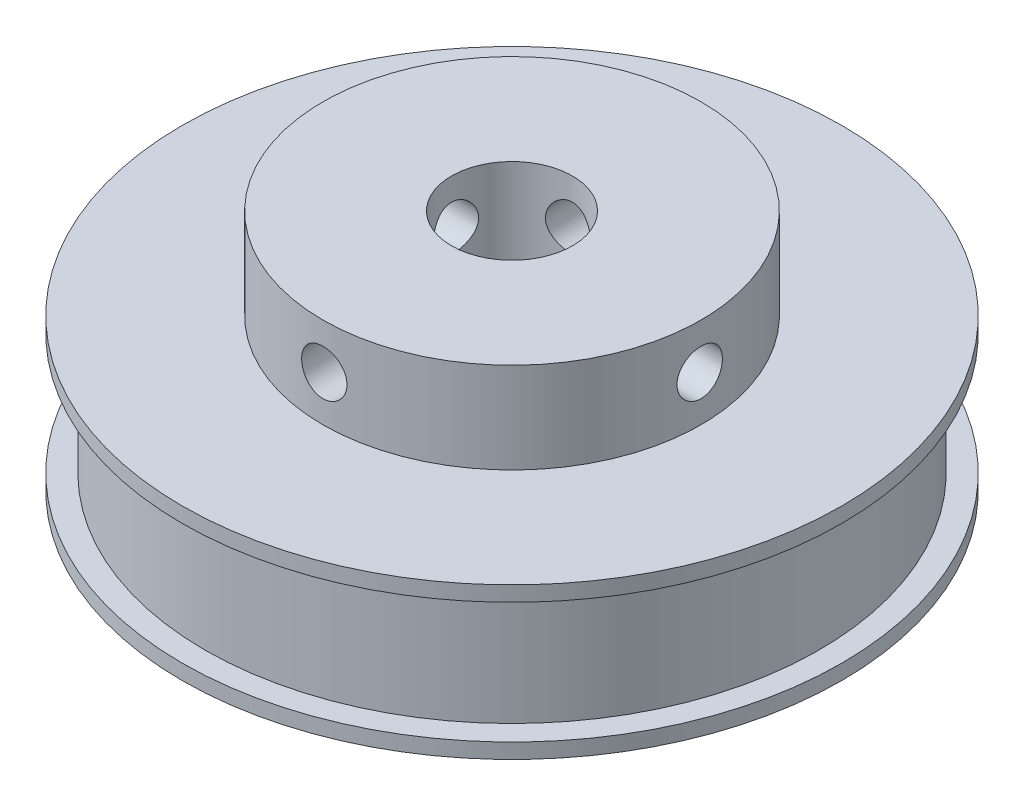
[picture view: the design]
ISO-10303-21;
HEADER;
FILE_DESCRIPTION(('STEP AP214'),'2;1');
FILE_NAME('part.step','',(''),(''),'','','');
FILE_SCHEMA(('AUTOMOTIVE_DESIGN { 1 0 10303 214 1 1 1 1 }'));
ENDSEC;
DATA;
#1=APPLICATION_CONTEXT('core data for automotive mechanical design processes');
#2=APPLICATION_PROTOCOL_DEFINITION('international standard','automotive_design',2000,#1);
#3=PRODUCT_CONTEXT('',#1,'mechanical');
#4=PRODUCT('Part','Part','',(#3));
#5=PRODUCT_RELATED_PRODUCT_CATEGORY('part','',(#4));
#6=PRODUCT_DEFINITION_FORMATION('','',#4);
#7=PRODUCT_DEFINITION_CONTEXT('part definition',#1,'design');
#8=PRODUCT_DEFINITION('design','',#6,#7);
#9=PRODUCT_DEFINITION_SHAPE('','',#8);
#10=(LENGTH_UNIT() NAMED_UNIT(*) SI_UNIT(.MILLI.,.METRE.));
#11=(NAMED_UNIT(*) PLANE_ANGLE_UNIT() SI_UNIT($,.RADIAN.));
#12=(NAMED_UNIT(*) SI_UNIT($,.STERADIAN.) SOLID_ANGLE_UNIT());
#13=UNCERTAINTY_MEASURE_WITH_UNIT(LENGTH_MEASURE(1.E-05),#10,'distance_accuracy_value','');
#14=(GEOMETRIC_REPRESENTATION_CONTEXT(3) GLOBAL_UNCERTAINTY_ASSIGNED_CONTEXT((#13)) GLOBAL_UNIT_ASSIGNED_CONTEXT((#10,
#11,#12)) REPRESENTATION_CONTEXT('',''));
#15=CARTESIAN_POINT('',(0.,0.,0.));
#16=DIRECTION('',(0.,0.,1.));
#17=DIRECTION('',(1.,0.,0.));
#18=AXIS2_PLACEMENT_3D('',#15,#16,#17);
#19=CARTESIAN_POINT('',(0.,16.,0.));
#20=DIRECTION('',(0.,-1.,0.));
#21=DIRECTION('',(0.,0.,-1.));
#22=AXIS2_PLACEMENT_3D('',#19,#20,#21);
#23=CYLINDRICAL_SURFACE('',#22,21.8);
#24=CARTESIAN_POINT('',(0.,0.,0.));
#25=DIRECTION('',(0.,1.,0.));
#26=DIRECTION('',(0.,0.,1.));
#27=AXIS2_PLACEMENT_3D('',#24,#25,#26);
#28=CIRCLE('',#27,21.8);
#29=CARTESIAN_POINT('',(0.,0.,21.8));
#30=VERTEX_POINT('',#29);
#31=EDGE_CURVE('E11',#30,#30,#28,.T.);
#32=ORIENTED_EDGE('',*,*,#31,.T.);
#33=EDGE_LOOP('',(#32));
#34=FACE_BOUND('',#33,.T.);
#35=CARTESIAN_POINT('',(0.,1.,0.));
#36=DIRECTION('',(0.,1.,0.));
#37=DIRECTION('',(0.,0.,1.));
#38=AXIS2_PLACEMENT_3D('',#35,#36,#37);
#39=CIRCLE('',#38,21.8);
#40=CARTESIAN_POINT('',(0.,1.,21.8));
#41=VERTEX_POINT('',#40);
#42=EDGE_CURVE('E69',#41,#41,#39,.T.);
#43=ORIENTED_EDGE('',*,*,#42,.F.);
#44=EDGE_LOOP('',(#43));
#45=FACE_BOUND('',#44,.T.);
#46=ADVANCED_FACE('F41',(#34,#45),#23,.T.);
#47=CARTESIAN_POINT('',(0.,9.,0.));
#48=DIRECTION('',(0.,1.,0.));
#49=DIRECTION('',(0.,0.,1.));
#50=AXIS2_PLACEMENT_3D('',#47,#48,#49);
#51=CIRCLE('',#50,21.8);
#52=CARTESIAN_POINT('',(0.,9.,21.8));
#53=VERTEX_POINT('',#52);
#54=EDGE_CURVE('E66',#53,#53,#51,.T.);
#55=ORIENTED_EDGE('',*,*,#54,.T.);
#56=EDGE_LOOP('',(#55));
#57=FACE_BOUND('',#56,.T.);
#58=CARTESIAN_POINT('',(0.,10.,0.));
#59=DIRECTION('',(0.,1.,0.));
#60=DIRECTION('',(0.,0.,1.));
#61=AXIS2_PLACEMENT_3D('',#58,#59,#60);
#62=CIRCLE('',#61,21.8);
#63=CARTESIAN_POINT('',(0.,10.,21.8));
#64=VERTEX_POINT('',#63);
#65=EDGE_CURVE('E65',#64,#64,#62,.T.);
#66=ORIENTED_EDGE('',*,*,#65,.F.);
#67=EDGE_LOOP('',(#66));
#68=FACE_BOUND('',#67,.T.);
#69=ADVANCED_FACE('F43',(#57,#68),#23,.T.);
#70=CARTESIAN_POINT('',(0.,16.,0.));
#71=DIRECTION('',(0.,1.,0.));
#72=DIRECTION('',(0.,0.,1.));
#73=AXIS2_PLACEMENT_3D('',#70,#71,#72);
#74=PLANE('',#73);
#75=CARTESIAN_POINT('',(0.,16.,0.));
#76=DIRECTION('',(0.,1.,0.));
#77=DIRECTION('',(0.,0.,1.));
#78=AXIS2_PLACEMENT_3D('',#75,#76,#77);
#79=CIRCLE('',#78,4.);
#80=CARTESIAN_POINT('',(0.,16.,4.));
#81=VERTEX_POINT('',#80);
#82=EDGE_CURVE('E56',#81,#81,#79,.T.);
#83=ORIENTED_EDGE('',*,*,#82,.F.);
#84=EDGE_LOOP('',(#83));
#85=FACE_BOUND('',#84,.T.);
#86=CARTESIAN_POINT('',(0.,16.,0.));
#87=DIRECTION('',(0.,1.,0.));
#88=DIRECTION('',(0.,0.,1.));
#89=AXIS2_PLACEMENT_3D('',#86,#87,#88);
#90=CIRCLE('',#89,12.5);
#91=CARTESIAN_POINT('',(0.,16.,12.5));
#92=VERTEX_POINT('',#91);
#93=EDGE_CURVE('E73',#92,#92,#90,.T.);
#94=ORIENTED_EDGE('',*,*,#93,.T.);
#95=EDGE_LOOP('',(#94));
#96=FACE_BOUND('',#95,.T.);
#97=ADVANCED_FACE('F127',(#85,#96),#74,.T.);
#98=CARTESIAN_POINT('',(0.,0.,0.));
#99=DIRECTION('',(0.,1.,0.));
#100=DIRECTION('',(0.,0.,1.));
#101=AXIS2_PLACEMENT_3D('',#98,#99,#100);
#102=PLANE('',#101);
#103=CARTESIAN_POINT('',(0.,0.,0.));
#104=DIRECTION('',(0.,1.,0.));
#105=DIRECTION('',(0.,0.,1.));
#106=AXIS2_PLACEMENT_3D('',#103,#104,#105);
#107=CIRCLE('',#106,4.);
#108=CARTESIAN_POINT('',(0.,0.,4.));
#109=VERTEX_POINT('',#108);
#110=EDGE_CURVE('E53',#109,#109,#107,.T.);
#111=ORIENTED_EDGE('',*,*,#110,.T.);
#112=EDGE_LOOP('',(#111));
#113=FACE_BOUND('',#112,.T.);
#114=ORIENTED_EDGE('',*,*,#31,.F.);
#115=EDGE_LOOP('',(#114));
#116=FACE_BOUND('',#115,.T.);
#117=ADVANCED_FACE('F130',(#113,#116),#102,.F.);
#118=CARTESIAN_POINT('',(0.,0.,0.));
#119=DIRECTION('',(0.,1.,0.));
#120=DIRECTION('',(0.,0.,1.));
#121=AXIS2_PLACEMENT_3D('',#118,#119,#120);
#122=CYLINDRICAL_SURFACE('',#121,4.);
#123=CARTESIAN_POINT('',(0.,11.5,4.));
#124=CARTESIAN_POINT('',(0.0812350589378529,11.4999970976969,4.00000217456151));
#125=CARTESIAN_POINT('',(0.162450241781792,11.5066197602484,3.99750379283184));
#126=CARTESIAN_POINT('',(0.322453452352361,11.5328281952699,3.98778696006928));
#127=CARTESIAN_POINT('',(0.401241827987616,11.5524121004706,3.98056918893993));
#128=CARTESIAN_POINT('',(0.554060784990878,11.6037530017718,3.96218832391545));
#129=CARTESIAN_POINT('',(0.628100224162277,11.6354865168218,3.9510328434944));
#130=CARTESIAN_POINT('',(0.769799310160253,11.7101064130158,3.92588767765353));
#131=CARTESIAN_POINT('',(0.837457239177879,11.7529957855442,3.91189723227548));
#132=CARTESIAN_POINT('',(0.967346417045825,11.8506125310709,3.88186246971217));
#133=CARTESIAN_POINT('',(1.02927073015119,11.9057302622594,3.86576002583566));
#134=CARTESIAN_POINT('',(1.14324421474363,12.0254104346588,3.83360220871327));
#135=CARTESIAN_POINT('',(1.19529036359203,12.0899757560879,3.81754685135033));
#136=CARTESIAN_POINT('',(1.28998202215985,12.2297174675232,3.78662470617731));
#137=CARTESIAN_POINT('',(1.3321939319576,12.3052043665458,3.77182648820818));
#138=CARTESIAN_POINT('',(1.40318646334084,12.4628483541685,3.74599860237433));
#139=CARTESIAN_POINT('',(1.43197244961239,12.5450027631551,3.73496742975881));
#140=CARTESIAN_POINT('',(1.47408431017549,12.7101167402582,3.71854412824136));
#141=CARTESIAN_POINT('',(1.48799593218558,12.7929050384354,3.71293924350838));
#142=CARTESIAN_POINT('',(1.50179556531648,12.9598161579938,3.70738061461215));
#143=CARTESIAN_POINT('',(1.5016893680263,13.0439384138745,3.70742453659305));
#144=CARTESIAN_POINT('',(1.48790429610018,13.205769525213,3.71297511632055));
#145=CARTESIAN_POINT('',(1.47503808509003,13.2835609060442,3.71815468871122));
#146=CARTESIAN_POINT('',(1.4374416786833,13.4357871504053,3.73284938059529));
#147=CARTESIAN_POINT('',(1.41270969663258,13.5102215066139,3.74236515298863));
#148=CARTESIAN_POINT('',(1.35163748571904,13.6552770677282,3.76485702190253));
#149=CARTESIAN_POINT('',(1.31508648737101,13.7257994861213,3.77789517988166));
#150=CARTESIAN_POINT('',(1.23156073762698,13.859945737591,3.80594210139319));
#151=CARTESIAN_POINT('',(1.18458238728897,13.9235671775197,3.82095154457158));
#152=CARTESIAN_POINT('',(1.07781780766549,14.0466036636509,3.85248038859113));
#153=CARTESIAN_POINT('',(1.01738298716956,14.1054486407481,3.86903347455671));
#154=CARTESIAN_POINT('',(0.887312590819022,14.2123379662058,3.90091728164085));
#155=CARTESIAN_POINT('',(0.817675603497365,14.2603806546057,3.91624781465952));
#156=CARTESIAN_POINT('',(0.66972343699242,14.3449303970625,3.9442639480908));
#157=CARTESIAN_POINT('',(0.591290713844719,14.3812475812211,3.95690498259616));
#158=CARTESIAN_POINT('',(0.428836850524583,14.43998260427,3.97778718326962));
#159=CARTESIAN_POINT('',(0.344818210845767,14.4624066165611,3.98603030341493));
#160=CARTESIAN_POINT('',(0.178375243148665,14.4916227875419,3.99684443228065));
#161=CARTESIAN_POINT('',(0.0961036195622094,14.4991826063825,3.99969369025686));
#162=CARTESIAN_POINT('',(-0.0685724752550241,14.5006910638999,4.00025893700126));
#163=CARTESIAN_POINT('',(-0.150976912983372,14.4946427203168,3.99797606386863));
#164=CARTESIAN_POINT('',(-0.310262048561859,14.4696899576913,3.98871709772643));
#165=CARTESIAN_POINT('',(-0.387233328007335,14.4512884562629,3.98192470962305));
#166=CARTESIAN_POINT('',(-0.53694175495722,14.4028139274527,3.96451477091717));
#167=CARTESIAN_POINT('',(-0.609678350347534,14.372739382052,3.9538967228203));
#168=CARTESIAN_POINT('',(-0.751247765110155,14.3008135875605,3.92949624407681));
#169=CARTESIAN_POINT('',(-0.819903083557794,14.2586422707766,3.91563000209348));
#170=CARTESIAN_POINT('',(-0.949392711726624,14.1640818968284,3.88626671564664));
#171=CARTESIAN_POINT('',(-1.01022412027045,14.1116890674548,3.87076907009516));
#172=CARTESIAN_POINT('',(-1.12603079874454,13.9945958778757,3.8387332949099));
#173=CARTESIAN_POINT('',(-1.18046154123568,13.9293578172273,3.82218696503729));
#174=CARTESIAN_POINT('',(-1.27771050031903,13.7903486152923,3.79078815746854));
#175=CARTESIAN_POINT('',(-1.32052767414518,13.7165767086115,3.77593583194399));
#176=CARTESIAN_POINT('',(-1.39337773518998,13.5619840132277,3.74966829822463));
#177=CARTESIAN_POINT('',(-1.42335685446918,13.4811352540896,3.73826760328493));
#178=CARTESIAN_POINT('',(-1.46907883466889,13.3149902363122,3.72054032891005));
#179=CARTESIAN_POINT('',(-1.48483050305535,13.2296967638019,3.71421061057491));
#180=CARTESIAN_POINT('',(-1.50086347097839,13.0629838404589,3.70775894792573));
#181=CARTESIAN_POINT('',(-1.50207331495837,12.9816673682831,3.70726444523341));
#182=CARTESIAN_POINT('',(-1.49136715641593,12.8200546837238,3.71158412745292));
#183=CARTESIAN_POINT('',(-1.47945239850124,12.7397583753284,3.71639780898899));
#184=CARTESIAN_POINT('',(-1.44355815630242,12.5849527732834,3.73048141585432));
#185=CARTESIAN_POINT('',(-1.41995798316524,12.5103416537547,3.73961085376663));
#186=CARTESIAN_POINT('',(-1.3616969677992,12.3660944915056,3.76121548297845));
#187=CARTESIAN_POINT('',(-1.32703332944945,12.2964597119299,3.77369151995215));
#188=CARTESIAN_POINT('',(-1.24552075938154,12.1601732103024,3.80139723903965));
#189=CARTESIAN_POINT('',(-1.1981283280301,12.0938692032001,3.81673698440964));
#190=CARTESIAN_POINT('',(-1.09334485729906,11.9698584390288,3.84806246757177));
#191=CARTESIAN_POINT('',(-1.03595064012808,11.9121544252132,3.86404840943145));
#192=CARTESIAN_POINT('',(-0.909080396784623,11.8037980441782,3.89590424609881));
#193=CARTESIAN_POINT('',(-0.839118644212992,11.7536962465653,3.91172104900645));
#194=CARTESIAN_POINT('',(-0.691213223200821,11.6659773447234,3.94054514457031));
#195=CARTESIAN_POINT('',(-0.613268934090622,11.6283612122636,3.95355221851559));
#196=CARTESIAN_POINT('',(-0.447999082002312,11.5656231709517,3.9757429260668));
#197=CARTESIAN_POINT('',(-0.360413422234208,11.5411129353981,3.98473657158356));
#198=CARTESIAN_POINT('',(-0.181875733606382,11.5083070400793,3.99686242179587));
#199=CARTESIAN_POINT('',(-0.090925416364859,11.5000032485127,3.99999756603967));
#200=CARTESIAN_POINT('',(0.,11.5,4.));
#201=B_SPLINE_CURVE_WITH_KNOTS('',3,(#123,#124,#125,#126,#127,#128,#129,#130,#131,#132,#133,
#134,#135,#136,#137,#138,#139,#140,#141,#142,#143,#144,#145,#146,#147,#148,#149,#150,#151,#152,
#153,#154,#155,#156,#157,#158,#159,#160,#161,#162,#163,#164,#165,#166,#167,#168,#169,#170,#171,
#172,#173,#174,#175,#176,#177,#178,#179,#180,#181,#182,#183,#184,#185,#186,#187,#188,#189,#190,
#191,#192,#193,#194,#195,#196,#197,#198,#199,#200),.UNSPECIFIED.,.T.,.F.,(4,2,2,2,2,2,2,2,2,2,2,
2,2,2,2,2,2,2,2,2,2,2,2,2,2,2,2,2,2,2,2,2,2,2,2,2,2,2,4),(0.,0.24336980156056,0.48670454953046,
0.729571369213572,0.972503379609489,1.22473618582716,1.47704604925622,1.73896674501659,
2.00078269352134,2.25185874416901,2.50283106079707,2.73878345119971,2.97477138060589,
3.21522408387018,3.45575990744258,3.71246153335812,3.96920257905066,4.22991375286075,
4.49050899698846,4.73725019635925,4.9839366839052,5.2211443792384,5.45838293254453,
5.70259221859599,5.94689180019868,6.20536519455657,6.46386178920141,6.72343066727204,
6.98283874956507,7.22558763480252,7.46831350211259,7.70363142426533,7.93900886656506,
8.18672471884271,8.43451941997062,8.69572329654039,8.95694749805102,9.22948515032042,
9.50188601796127),.UNSPECIFIED.);
#202=CARTESIAN_POINT('',(0.,11.5,4.));
#203=VERTEX_POINT('',#202);
#204=EDGE_CURVE('E85',#203,#203,#201,.T.);
#205=ORIENTED_EDGE('',*,*,#204,.T.);
#206=EDGE_LOOP('',(#205));
#207=FACE_BOUND('',#206,.T.);
#208=CARTESIAN_POINT('',(1.5,13.,-3.70809924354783));
#209=CARTESIAN_POINT('',(1.50000304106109,12.9189925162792,-3.70809640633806));
#210=CARTESIAN_POINT('',(1.49341597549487,12.8380050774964,-3.71078260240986));
#211=CARTESIAN_POINT('',(1.46736187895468,12.6784719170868,-3.72116159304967));
#212=CARTESIAN_POINT('',(1.44789523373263,12.599926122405,-3.72885423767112));
#213=CARTESIAN_POINT('',(1.39689657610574,12.4476246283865,-3.748254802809));
#214=CARTESIAN_POINT('',(1.36539347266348,12.3738579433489,-3.7599530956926));
#215=CARTESIAN_POINT('',(1.29131856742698,12.2326281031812,-3.78603134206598));
#216=CARTESIAN_POINT('',(1.24874344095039,12.1651668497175,-3.80041210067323));
#217=CARTESIAN_POINT('',(1.15146661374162,12.0351096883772,-3.83103574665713));
#218=CARTESIAN_POINT('',(1.09630381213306,11.9728714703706,-3.84733341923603));
#219=CARTESIAN_POINT('',(0.976395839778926,11.8582771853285,-3.87949750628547));
#220=CARTESIAN_POINT('',(0.91164863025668,11.8059232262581,-3.89536382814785));
#221=CARTESIAN_POINT('',(0.7716946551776,11.7108604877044,-3.92552873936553));
#222=CARTESIAN_POINT('',(0.696206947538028,11.6685405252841,-3.93975561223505));
#223=CARTESIAN_POINT('',(0.538555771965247,11.5973488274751,-3.96438007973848));
#224=CARTESIAN_POINT('',(0.456394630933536,11.568472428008,-3.97477900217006));
#225=CARTESIAN_POINT('',(0.291489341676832,11.5262421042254,-3.9901869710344));
#226=CARTESIAN_POINT('',(0.208923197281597,11.5122723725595,-3.99540915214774));
#227=CARTESIAN_POINT('',(0.0424643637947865,11.498278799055,-4.0006401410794));
#228=CARTESIAN_POINT('',(-0.0414278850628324,11.4982504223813,-4.00065064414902));
#229=CARTESIAN_POINT('',(-0.203743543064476,11.5117817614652,-3.99559265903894));
#230=CARTESIAN_POINT('',(-0.2822321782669,11.5246692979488,-3.99077541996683));
#231=CARTESIAN_POINT('',(-0.435839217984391,11.5625359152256,-3.97693274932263));
#232=CARTESIAN_POINT('',(-0.510957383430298,11.587515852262,-3.96790701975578));
#233=CARTESIAN_POINT('',(-0.656989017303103,11.6491704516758,-3.94637769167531));
#234=CARTESIAN_POINT('',(-0.727825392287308,11.6860100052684,-3.93382539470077));
#235=CARTESIAN_POINT('',(-0.862486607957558,11.7701920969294,-3.90651310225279));
#236=CARTESIAN_POINT('',(-0.926309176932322,11.8175380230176,-3.8917523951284));
#237=CARTESIAN_POINT('',(-1.04909048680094,11.9246272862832,-3.86052529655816));
#238=CARTESIAN_POINT('',(-1.10754614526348,11.9849339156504,-3.84400963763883));
#239=CARTESIAN_POINT('',(-1.21370395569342,12.1145929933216,-3.81182460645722));
#240=CARTESIAN_POINT('',(-1.261403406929,12.1839477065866,-3.79615544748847));
#241=CARTESIAN_POINT('',(-1.34565611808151,12.3317194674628,-3.76712703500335));
#242=CARTESIAN_POINT('',(-1.38193847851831,12.4103034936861,-3.75382677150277));
#243=CARTESIAN_POINT('',(-1.44056464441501,12.5730962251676,-3.73172438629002));
#244=CARTESIAN_POINT('',(-1.46291620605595,12.6573017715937,-3.72291976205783));
#245=CARTESIAN_POINT('',(-1.49190191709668,12.823975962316,-3.71139597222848));
#246=CARTESIAN_POINT('',(-1.49933521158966,12.9062841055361,-3.70836785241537));
#247=CARTESIAN_POINT('',(-1.50057885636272,13.0710093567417,-3.70786539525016));
#248=CARTESIAN_POINT('',(-1.49439261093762,13.1534264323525,-3.71038967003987));
#249=CARTESIAN_POINT('',(-1.46929733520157,13.3119299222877,-3.72039381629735));
#250=CARTESIAN_POINT('',(-1.45100618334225,13.3881311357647,-3.72763276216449));
#251=CARTESIAN_POINT('',(-1.40299774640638,13.5363479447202,-3.74596487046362));
#252=CARTESIAN_POINT('',(-1.37327812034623,13.6083626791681,-3.75705882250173));
#253=CARTESIAN_POINT('',(-1.30200292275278,13.7491644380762,-3.7823624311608));
#254=CARTESIAN_POINT('',(-1.26004545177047,13.8177292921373,-3.79667328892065));
#255=CARTESIAN_POINT('',(-1.16591317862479,13.947128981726,-3.82662814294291));
#256=CARTESIAN_POINT('',(-1.11373463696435,14.0079609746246,-3.84227262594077));
#257=CARTESIAN_POINT('',(-0.996727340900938,14.1241683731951,-3.87433046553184));
#258=CARTESIAN_POINT('',(-0.931306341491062,14.1789534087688,-3.89072969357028));
#259=CARTESIAN_POINT('',(-0.791797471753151,14.2768383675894,-3.92149874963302));
#260=CARTESIAN_POINT('',(-0.717709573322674,14.3199382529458,-3.93586857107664));
#261=CARTESIAN_POINT('',(-0.563016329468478,14.3929460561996,-3.96094985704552));
#262=CARTESIAN_POINT('',(-0.482434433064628,14.4228991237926,-3.9716738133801));
#263=CARTESIAN_POINT('',(-0.316881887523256,14.4686564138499,-3.98829436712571));
#264=CARTESIAN_POINT('',(-0.231913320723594,14.4844672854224,-3.99419323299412));
#265=CARTESIAN_POINT('',(-0.0653355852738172,14.5007744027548,-4.00028407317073));
#266=CARTESIAN_POINT('',(0.0161807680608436,14.502109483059,-4.00078860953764));
#267=CARTESIAN_POINT('',(0.178226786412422,14.4915848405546,-3.99684889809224));
#268=CARTESIAN_POINT('',(0.258756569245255,14.4797267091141,-3.9924052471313));
#269=CARTESIAN_POINT('',(0.414548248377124,14.4437411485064,-3.97921089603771));
#270=CARTESIAN_POINT('',(0.489890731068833,14.4199200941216,-3.97056791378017));
#271=CARTESIAN_POINT('',(0.635515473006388,14.3609899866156,-3.9498778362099));
#272=CARTESIAN_POINT('',(0.705796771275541,14.3258787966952,-3.93783009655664));
#273=CARTESIAN_POINT('',(0.842540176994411,14.2436860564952,-3.91090618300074));
#274=CARTESIAN_POINT('',(0.908717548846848,14.1961633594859,-3.89593240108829));
#275=CARTESIAN_POINT('',(1.03241734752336,14.0911921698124,-3.86499507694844));
#276=CARTESIAN_POINT('',(1.0899366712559,14.0337401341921,-3.84903118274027));
#277=CARTESIAN_POINT('',(1.19781214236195,13.9069358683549,-3.81688129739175));
#278=CARTESIAN_POINT('',(1.24762999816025,13.8371155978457,-3.8007280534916));
#279=CARTESIAN_POINT('',(1.33484709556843,13.6895841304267,-3.77098325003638));
#280=CARTESIAN_POINT('',(1.37224504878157,13.6118721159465,-3.75739195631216));
#281=CARTESIAN_POINT('',(1.4346588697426,13.4470443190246,-3.73402269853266));
#282=CARTESIAN_POINT('',(1.45906002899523,13.3596656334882,-3.7244380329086));
#283=CARTESIAN_POINT('',(1.49172356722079,13.1815147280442,-3.71147994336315));
#284=CARTESIAN_POINT('',(1.49999659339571,13.09074478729,-3.70810242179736));
#285=CARTESIAN_POINT('',(1.5,13.,-3.70809924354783));
#286=B_SPLINE_CURVE_WITH_KNOTS('',3,(#208,#209,#210,#211,#212,#213,#214,#215,#216,#217,#218,
#219,#220,#221,#222,#223,#224,#225,#226,#227,#228,#229,#230,#231,#232,#233,#234,#235,#236,#237,
#238,#239,#240,#241,#242,#243,#244,#245,#246,#247,#248,#249,#250,#251,#252,#253,#254,#255,#256,
#257,#258,#259,#260,#261,#262,#263,#264,#265,#266,#267,#268,#269,#270,#271,#272,#273,#274,#275,
#276,#277,#278,#279,#280,#281,#282,#283,#284,#285),.UNSPECIFIED.,.T.,.F.,(4,2,2,2,2,2,2,2,2,2,2,
2,2,2,2,2,2,2,2,2,2,2,2,2,2,2,2,2,2,2,2,2,2,2,2,2,2,2,4),(0.,0.242684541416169,
0.485361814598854,0.72745985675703,0.969630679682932,1.22274652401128,1.47591628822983,
1.73770072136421,1.9993942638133,2.24980018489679,2.50012465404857,2.73806472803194,
2.97602165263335,3.21744131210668,3.45893893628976,3.71456675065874,3.97025867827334,
4.23162592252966,4.49284751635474,4.73965657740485,4.98640395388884,5.22143845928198,
5.45652113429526,5.70041561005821,5.94439948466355,6.20385016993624,6.46330169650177,
6.72185508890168,6.98028685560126,7.22365720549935,7.46699820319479,7.7044027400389,
7.94185223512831,8.18928323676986,8.43680270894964,8.69738599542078,8.95799630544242,
9.23003178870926,9.50188762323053),.UNSPECIFIED.);
#287=CARTESIAN_POINT('',(1.5,13.,-3.70809924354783));
#288=VERTEX_POINT('',#287);
#289=EDGE_CURVE('E135',#288,#288,#286,.T.);
#290=ORIENTED_EDGE('',*,*,#289,.T.);
#291=EDGE_LOOP('',(#290));
#292=FACE_BOUND('',#291,.T.);
#293=CARTESIAN_POINT('',(-3.70809924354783,13.,-1.5));
#294=CARTESIAN_POINT('',(-3.70809640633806,12.9189925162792,-1.50000304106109));
#295=CARTESIAN_POINT('',(-3.71078260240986,12.8380050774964,-1.49341597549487));
#296=CARTESIAN_POINT('',(-3.72116159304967,12.6784719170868,-1.46736187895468));
#297=CARTESIAN_POINT('',(-3.72885423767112,12.599926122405,-1.44789523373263));
#298=CARTESIAN_POINT('',(-3.748254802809,12.4476246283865,-1.39689657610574));
#299=CARTESIAN_POINT('',(-3.7599530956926,12.3738579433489,-1.36539347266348));
#300=CARTESIAN_POINT('',(-3.78603134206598,12.2326281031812,-1.29131856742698));
#301=CARTESIAN_POINT('',(-3.80041210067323,12.1651668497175,-1.24874344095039));
#302=CARTESIAN_POINT('',(-3.83103574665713,12.0351096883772,-1.15146661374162));
#303=CARTESIAN_POINT('',(-3.84733341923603,11.9728714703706,-1.09630381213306));
#304=CARTESIAN_POINT('',(-3.87949750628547,11.8582771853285,-0.976395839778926));
#305=CARTESIAN_POINT('',(-3.89536382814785,11.8059232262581,-0.911648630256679));
#306=CARTESIAN_POINT('',(-3.92552873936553,11.7108604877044,-0.7716946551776));
#307=CARTESIAN_POINT('',(-3.93975561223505,11.6685405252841,-0.696206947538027));
#308=CARTESIAN_POINT('',(-3.96438007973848,11.5973488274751,-0.538555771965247));
#309=CARTESIAN_POINT('',(-3.97477900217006,11.568472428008,-0.456394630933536));
#310=CARTESIAN_POINT('',(-3.9901869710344,11.5262421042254,-0.291489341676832));
#311=CARTESIAN_POINT('',(-3.99540915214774,11.5122723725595,-0.208923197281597));
#312=CARTESIAN_POINT('',(-4.0006401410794,11.498278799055,-0.0424643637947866));
#313=CARTESIAN_POINT('',(-4.00065064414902,11.4982504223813,0.0414278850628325));
#314=CARTESIAN_POINT('',(-3.99559265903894,11.5117817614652,0.203743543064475));
#315=CARTESIAN_POINT('',(-3.99077541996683,11.5246692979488,0.2822321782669));
#316=CARTESIAN_POINT('',(-3.97693274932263,11.5625359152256,0.435839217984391));
#317=CARTESIAN_POINT('',(-3.96790701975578,11.587515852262,0.510957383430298));
#318=CARTESIAN_POINT('',(-3.94637769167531,11.6491704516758,0.656989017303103));
#319=CARTESIAN_POINT('',(-3.93382539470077,11.6860100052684,0.727825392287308));
#320=CARTESIAN_POINT('',(-3.90651310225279,11.7701920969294,0.862486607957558));
#321=CARTESIAN_POINT('',(-3.8917523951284,11.8175380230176,0.926309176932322));
#322=CARTESIAN_POINT('',(-3.86052529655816,11.9246272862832,1.04909048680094));
#323=CARTESIAN_POINT('',(-3.84400963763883,11.9849339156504,1.10754614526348));
#324=CARTESIAN_POINT('',(-3.81182460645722,12.1145929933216,1.21370395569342));
#325=CARTESIAN_POINT('',(-3.79615544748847,12.1839477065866,1.261403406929));
#326=CARTESIAN_POINT('',(-3.76712703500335,12.3317194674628,1.34565611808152));
#327=CARTESIAN_POINT('',(-3.75382677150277,12.4103034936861,1.38193847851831));
#328=CARTESIAN_POINT('',(-3.73172438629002,12.5730962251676,1.44056464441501));
#329=CARTESIAN_POINT('',(-3.72291976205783,12.6573017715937,1.46291620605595));
#330=CARTESIAN_POINT('',(-3.71139597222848,12.823975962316,1.49190191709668));
#331=CARTESIAN_POINT('',(-3.70836785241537,12.9062841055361,1.49933521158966));
#332=CARTESIAN_POINT('',(-3.70786539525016,13.0710093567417,1.50057885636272));
#333=CARTESIAN_POINT('',(-3.71038967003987,13.1534264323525,1.49439261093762));
#334=CARTESIAN_POINT('',(-3.72039381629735,13.3119299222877,1.46929733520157));
#335=CARTESIAN_POINT('',(-3.72763276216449,13.3881311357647,1.45100618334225));
#336=CARTESIAN_POINT('',(-3.74596487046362,13.5363479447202,1.40299774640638));
#337=CARTESIAN_POINT('',(-3.75705882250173,13.6083626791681,1.37327812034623));
#338=CARTESIAN_POINT('',(-3.7823624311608,13.7491644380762,1.30200292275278));
#339=CARTESIAN_POINT('',(-3.79667328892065,13.8177292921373,1.26004545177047));
#340=CARTESIAN_POINT('',(-3.82662814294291,13.947128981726,1.16591317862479));
#341=CARTESIAN_POINT('',(-3.84227262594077,14.0079609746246,1.11373463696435));
#342=CARTESIAN_POINT('',(-3.87433046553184,14.1241683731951,0.996727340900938));
#343=CARTESIAN_POINT('',(-3.89072969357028,14.1789534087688,0.931306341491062));
#344=CARTESIAN_POINT('',(-3.92149874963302,14.2768383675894,0.791797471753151));
#345=CARTESIAN_POINT('',(-3.93586857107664,14.3199382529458,0.717709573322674));
#346=CARTESIAN_POINT('',(-3.96094985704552,14.3929460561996,0.563016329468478));
#347=CARTESIAN_POINT('',(-3.9716738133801,14.4228991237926,0.482434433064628));
#348=CARTESIAN_POINT('',(-3.98829436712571,14.4686564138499,0.316881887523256));
#349=CARTESIAN_POINT('',(-3.99419323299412,14.4844672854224,0.231913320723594));
#350=CARTESIAN_POINT('',(-4.00028407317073,14.5007744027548,0.0653355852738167));
#351=CARTESIAN_POINT('',(-4.00078860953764,14.502109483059,-0.016180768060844));
#352=CARTESIAN_POINT('',(-3.99684889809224,14.4915848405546,-0.178226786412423));
#353=CARTESIAN_POINT('',(-3.9924052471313,14.4797267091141,-0.258756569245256));
#354=CARTESIAN_POINT('',(-3.97921089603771,14.4437411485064,-0.414548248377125));
#355=CARTESIAN_POINT('',(-3.97056791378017,14.4199200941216,-0.489890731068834));
#356=CARTESIAN_POINT('',(-3.9498778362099,14.3609899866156,-0.635515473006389));
#357=CARTESIAN_POINT('',(-3.93783009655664,14.3258787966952,-0.705796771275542));
#358=CARTESIAN_POINT('',(-3.91090618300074,14.2436860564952,-0.842540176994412));
#359=CARTESIAN_POINT('',(-3.89593240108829,14.1961633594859,-0.908717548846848));
#360=CARTESIAN_POINT('',(-3.86499507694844,14.0911921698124,-1.03241734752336));
#361=CARTESIAN_POINT('',(-3.84903118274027,14.0337401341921,-1.0899366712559));
#362=CARTESIAN_POINT('',(-3.81688129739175,13.9069358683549,-1.19781214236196));
#363=CARTESIAN_POINT('',(-3.8007280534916,13.8371155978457,-1.24762999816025));
#364=CARTESIAN_POINT('',(-3.77098325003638,13.6895841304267,-1.33484709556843));
#365=CARTESIAN_POINT('',(-3.75739195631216,13.6118721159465,-1.37224504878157));
#366=CARTESIAN_POINT('',(-3.73402269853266,13.4470443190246,-1.4346588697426));
#367=CARTESIAN_POINT('',(-3.7244380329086,13.3596656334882,-1.45906002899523));
#368=CARTESIAN_POINT('',(-3.71147994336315,13.1815147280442,-1.49172356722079));
#369=CARTESIAN_POINT('',(-3.70810242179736,13.09074478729,-1.49999659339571));
#370=CARTESIAN_POINT('',(-3.70809924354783,13.,-1.5));
#371=B_SPLINE_CURVE_WITH_KNOTS('',3,(#293,#294,#295,#296,#297,#298,#299,#300,#301,#302,#303,
#304,#305,#306,#307,#308,#309,#310,#311,#312,#313,#314,#315,#316,#317,#318,#319,#320,#321,#322,
#323,#324,#325,#326,#327,#328,#329,#330,#331,#332,#333,#334,#335,#336,#337,#338,#339,#340,#341,
#342,#343,#344,#345,#346,#347,#348,#349,#350,#351,#352,#353,#354,#355,#356,#357,#358,#359,#360,
#361,#362,#363,#364,#365,#366,#367,#368,#369,#370),.UNSPECIFIED.,.T.,.F.,(4,2,2,2,2,2,2,2,2,2,2,
2,2,2,2,2,2,2,2,2,2,2,2,2,2,2,2,2,2,2,2,2,2,2,2,2,2,2,4),(0.,0.242684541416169,
0.485361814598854,0.727459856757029,0.969630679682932,1.22274652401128,1.47591628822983,
1.73770072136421,1.9993942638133,2.24980018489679,2.50012465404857,2.73806472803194,
2.97602165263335,3.21744131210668,3.45893893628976,3.71456675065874,3.97025867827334,
4.23162592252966,4.49284751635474,4.73965657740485,4.98640395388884,5.22143845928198,
5.45652113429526,5.70041561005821,5.94439948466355,6.20385016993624,6.46330169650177,
6.72185508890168,6.98028685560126,7.22365720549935,7.46699820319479,7.7044027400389,
7.94185223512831,8.18928323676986,8.43680270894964,8.69738599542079,8.95799630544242,
9.23003178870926,9.50188762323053),.UNSPECIFIED.);
#372=CARTESIAN_POINT('',(-3.70809924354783,13.,-1.5));
#373=VERTEX_POINT('',#372);
#374=EDGE_CURVE('E112',#373,#373,#371,.T.);
#375=ORIENTED_EDGE('',*,*,#374,.T.);
#376=EDGE_LOOP('',(#375));
#377=FACE_BOUND('',#376,.T.);
#378=CARTESIAN_POINT('',(3.70809924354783,13.,-1.5));
#379=CARTESIAN_POINT('',(3.70809640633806,13.0810074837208,-1.50000304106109));
#380=CARTESIAN_POINT('',(3.71078260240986,13.1619949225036,-1.49341597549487));
#381=CARTESIAN_POINT('',(3.72116159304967,13.3215280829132,-1.46736187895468));
#382=CARTESIAN_POINT('',(3.72885423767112,13.400073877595,-1.44789523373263));
#383=CARTESIAN_POINT('',(3.748254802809,13.5523753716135,-1.39689657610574));
#384=CARTESIAN_POINT('',(3.7599530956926,13.6261420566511,-1.36539347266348));
#385=CARTESIAN_POINT('',(3.78603134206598,13.7673718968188,-1.29131856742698));
#386=CARTESIAN_POINT('',(3.80041210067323,13.8348331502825,-1.24874344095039));
#387=CARTESIAN_POINT('',(3.83103574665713,13.9648903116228,-1.15146661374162));
#388=CARTESIAN_POINT('',(3.84733341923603,14.0271285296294,-1.09630381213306));
#389=CARTESIAN_POINT('',(3.87949750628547,14.1417228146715,-0.976395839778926));
#390=CARTESIAN_POINT('',(3.89536382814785,14.1940767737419,-0.911648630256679));
#391=CARTESIAN_POINT('',(3.92552873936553,14.2891395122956,-0.7716946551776));
#392=CARTESIAN_POINT('',(3.93975561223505,14.3314594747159,-0.696206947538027));
#393=CARTESIAN_POINT('',(3.96438007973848,14.4026511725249,-0.538555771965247));
#394=CARTESIAN_POINT('',(3.97477900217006,14.431527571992,-0.456394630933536));
#395=CARTESIAN_POINT('',(3.9901869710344,14.4737578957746,-0.291489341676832));
#396=CARTESIAN_POINT('',(3.99540915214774,14.4877276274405,-0.208923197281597));
#397=CARTESIAN_POINT('',(4.0006401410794,14.501721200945,-0.0424643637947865));
#398=CARTESIAN_POINT('',(4.00065064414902,14.5017495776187,0.0414278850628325));
#399=CARTESIAN_POINT('',(3.99559265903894,14.4882182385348,0.203743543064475));
#400=CARTESIAN_POINT('',(3.99077541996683,14.4753307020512,0.2822321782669));
#401=CARTESIAN_POINT('',(3.97693274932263,14.4374640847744,0.435839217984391));
#402=CARTESIAN_POINT('',(3.96790701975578,14.412484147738,0.510957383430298));
#403=CARTESIAN_POINT('',(3.94637769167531,14.3508295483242,0.656989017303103));
#404=CARTESIAN_POINT('',(3.93382539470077,14.3139899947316,0.727825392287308));
#405=CARTESIAN_POINT('',(3.90651310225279,14.2298079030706,0.862486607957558));
#406=CARTESIAN_POINT('',(3.8917523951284,14.1824619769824,0.926309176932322));
#407=CARTESIAN_POINT('',(3.86052529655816,14.0753727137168,1.04909048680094));
#408=CARTESIAN_POINT('',(3.84400963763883,14.0150660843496,1.10754614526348));
#409=CARTESIAN_POINT('',(3.81182460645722,13.8854070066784,1.21370395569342));
#410=CARTESIAN_POINT('',(3.79615544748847,13.8160522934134,1.261403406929));
#411=CARTESIAN_POINT('',(3.76712703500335,13.6682805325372,1.34565611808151));
#412=CARTESIAN_POINT('',(3.75382677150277,13.5896965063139,1.38193847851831));
#413=CARTESIAN_POINT('',(3.73172438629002,13.4269037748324,1.44056464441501));
#414=CARTESIAN_POINT('',(3.72291976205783,13.3426982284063,1.46291620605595));
#415=CARTESIAN_POINT('',(3.71139597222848,13.176024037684,1.49190191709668));
#416=CARTESIAN_POINT('',(3.70836785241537,13.0937158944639,1.49933521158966));
#417=CARTESIAN_POINT('',(3.70786539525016,12.9289906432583,1.50057885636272));
#418=CARTESIAN_POINT('',(3.71038967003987,12.8465735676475,1.49439261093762));
#419=CARTESIAN_POINT('',(3.72039381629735,12.6880700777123,1.46929733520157));
#420=CARTESIAN_POINT('',(3.72763276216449,12.6118688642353,1.45100618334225));
#421=CARTESIAN_POINT('',(3.74596487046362,12.4636520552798,1.40299774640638));
#422=CARTESIAN_POINT('',(3.75705882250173,12.3916373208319,1.37327812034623));
#423=CARTESIAN_POINT('',(3.7823624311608,12.2508355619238,1.30200292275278));
#424=CARTESIAN_POINT('',(3.79667328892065,12.1822707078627,1.26004545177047));
#425=CARTESIAN_POINT('',(3.82662814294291,12.052871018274,1.16591317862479));
#426=CARTESIAN_POINT('',(3.84227262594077,11.9920390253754,1.11373463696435));
#427=CARTESIAN_POINT('',(3.87433046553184,11.8758316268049,0.996727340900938));
#428=CARTESIAN_POINT('',(3.89072969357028,11.8210465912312,0.931306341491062));
#429=CARTESIAN_POINT('',(3.92149874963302,11.7231616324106,0.791797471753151));
#430=CARTESIAN_POINT('',(3.93586857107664,11.6800617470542,0.717709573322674));
#431=CARTESIAN_POINT('',(3.96094985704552,11.6070539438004,0.563016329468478));
#432=CARTESIAN_POINT('',(3.9716738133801,11.5771008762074,0.482434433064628));
#433=CARTESIAN_POINT('',(3.98829436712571,11.5313435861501,0.316881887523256));
#434=CARTESIAN_POINT('',(3.99419323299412,11.5155327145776,0.231913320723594));
#435=CARTESIAN_POINT('',(4.00028407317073,11.4992255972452,0.0653355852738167));
#436=CARTESIAN_POINT('',(4.00078860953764,11.497890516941,-0.016180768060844));
#437=CARTESIAN_POINT('',(3.99684889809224,11.5084151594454,-0.178226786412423));
#438=CARTESIAN_POINT('',(3.9924052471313,11.5202732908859,-0.258756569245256));
#439=CARTESIAN_POINT('',(3.97921089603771,11.5562588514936,-0.414548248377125));
#440=CARTESIAN_POINT('',(3.97056791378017,11.5800799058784,-0.489890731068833));
#441=CARTESIAN_POINT('',(3.9498778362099,11.6390100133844,-0.635515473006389));
#442=CARTESIAN_POINT('',(3.93783009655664,11.6741212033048,-0.705796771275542));
#443=CARTESIAN_POINT('',(3.91090618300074,11.7563139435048,-0.842540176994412));
#444=CARTESIAN_POINT('',(3.89593240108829,11.8038366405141,-0.908717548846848));
#445=CARTESIAN_POINT('',(3.86499507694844,11.9088078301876,-1.03241734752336));
#446=CARTESIAN_POINT('',(3.84903118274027,11.9662598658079,-1.0899366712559));
#447=CARTESIAN_POINT('',(3.81688129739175,12.0930641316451,-1.19781214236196));
#448=CARTESIAN_POINT('',(3.8007280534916,12.1628844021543,-1.24762999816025));
#449=CARTESIAN_POINT('',(3.77098325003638,12.3104158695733,-1.33484709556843));
#450=CARTESIAN_POINT('',(3.75739195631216,12.3881278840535,-1.37224504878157));
#451=CARTESIAN_POINT('',(3.73402269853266,12.5529556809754,-1.4346588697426));
#452=CARTESIAN_POINT('',(3.7244380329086,12.6403343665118,-1.45906002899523));
#453=CARTESIAN_POINT('',(3.71147994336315,12.8184852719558,-1.49172356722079));
#454=CARTESIAN_POINT('',(3.70810242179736,12.90925521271,-1.49999659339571));
#455=CARTESIAN_POINT('',(3.70809924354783,13.,-1.5));
#456=B_SPLINE_CURVE_WITH_KNOTS('',3,(#378,#379,#380,#381,#382,#383,#384,#385,#386,#387,#388,
#389,#390,#391,#392,#393,#394,#395,#396,#397,#398,#399,#400,#401,#402,#403,#404,#405,#406,#407,
#408,#409,#410,#411,#412,#413,#414,#415,#416,#417,#418,#419,#420,#421,#422,#423,#424,#425,#426,
#427,#428,#429,#430,#431,#432,#433,#434,#435,#436,#437,#438,#439,#440,#441,#442,#443,#444,#445,
#446,#447,#448,#449,#450,#451,#452,#453,#454,#455),.UNSPECIFIED.,.T.,.F.,(4,2,2,2,2,2,2,2,2,2,2,
2,2,2,2,2,2,2,2,2,2,2,2,2,2,2,2,2,2,2,2,2,2,2,2,2,2,2,4),(0.,0.242684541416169,
0.485361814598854,0.727459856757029,0.969630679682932,1.22274652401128,1.47591628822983,
1.73770072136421,1.9993942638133,2.24980018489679,2.50012465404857,2.73806472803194,
2.97602165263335,3.21744131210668,3.45893893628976,3.71456675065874,3.97025867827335,
4.23162592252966,4.49284751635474,4.73965657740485,4.98640395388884,5.22143845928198,
5.45652113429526,5.70041561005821,5.94439948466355,6.20385016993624,6.46330169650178,
6.72185508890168,6.98028685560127,7.22365720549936,7.4669982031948,7.7044027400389,
7.94185223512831,8.18928323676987,8.43680270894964,8.69738599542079,8.95799630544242,
9.23003178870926,9.50188762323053),.UNSPECIFIED.);
#457=CARTESIAN_POINT('',(3.70809924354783,13.,-1.5));
#458=VERTEX_POINT('',#457);
#459=EDGE_CURVE('E110',#458,#458,#456,.T.);
#460=ORIENTED_EDGE('',*,*,#459,.T.);
#461=EDGE_LOOP('',(#460));
#462=FACE_BOUND('',#461,.T.);
#463=ORIENTED_EDGE('',*,*,#110,.F.);
#464=EDGE_LOOP('',(#463));
#465=FACE_BOUND('',#464,.T.);
#466=ORIENTED_EDGE('',*,*,#82,.T.);
#467=EDGE_LOOP('',(#466));
#468=FACE_BOUND('',#467,.T.);
#469=ADVANCED_FACE('F124',(#207,#292,#377,#462,#465,#468),#122,.F.);
#470=CARTESIAN_POINT('',(0.,10.,0.));
#471=DIRECTION('',(0.,1.,0.));
#472=DIRECTION('',(0.,0.,1.));
#473=AXIS2_PLACEMENT_3D('',#470,#471,#472);
#474=PLANE('',#473);
#475=CARTESIAN_POINT('',(0.,10.,0.));
#476=DIRECTION('',(0.,1.,0.));
#477=DIRECTION('',(0.,0.,1.));
#478=AXIS2_PLACEMENT_3D('',#475,#476,#477);
#479=CIRCLE('',#478,12.5);
#480=CARTESIAN_POINT('',(0.,10.,12.5));
#481=VERTEX_POINT('',#480);
#482=EDGE_CURVE('E68',#481,#481,#479,.T.);
#483=ORIENTED_EDGE('',*,*,#482,.F.);
#484=EDGE_LOOP('',(#483));
#485=FACE_BOUND('',#484,.T.);
#486=ORIENTED_EDGE('',*,*,#65,.T.);
#487=EDGE_LOOP('',(#486));
#488=FACE_BOUND('',#487,.T.);
#489=ADVANCED_FACE('F126',(#485,#488),#474,.T.);
#490=CARTESIAN_POINT('',(0.,10.,0.));
#491=DIRECTION('',(0.,1.,0.));
#492=DIRECTION('',(0.,0.,1.));
#493=AXIS2_PLACEMENT_3D('',#490,#491,#492);
#494=CYLINDRICAL_SURFACE('',#493,12.5);
#495=CARTESIAN_POINT('',(0.,11.5,12.5));
#496=CARTESIAN_POINT('',(0.0839320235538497,11.5000035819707,12.499998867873));
#497=CARTESIAN_POINT('',(0.167917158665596,11.5070683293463,12.4991457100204));
#498=CARTESIAN_POINT('',(0.333552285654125,11.5351405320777,12.495824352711));
#499=CARTESIAN_POINT('',(0.415199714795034,11.5561627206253,12.4933544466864));
#500=CARTESIAN_POINT('',(0.573737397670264,11.611523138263,12.4870779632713));
#501=CARTESIAN_POINT('',(0.650630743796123,11.6458526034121,12.4832722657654));
#502=CARTESIAN_POINT('',(0.797549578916,11.7268343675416,12.4747479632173));
#503=CARTESIAN_POINT('',(0.867576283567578,11.7734844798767,12.4700295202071));
#504=CARTESIAN_POINT('',(0.999145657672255,11.8780374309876,12.460180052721));
#505=CARTESIAN_POINT('',(1.0606483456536,11.935990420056,12.4550472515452));
#506=CARTESIAN_POINT('',(1.17307965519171,12.0613964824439,12.4449619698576));
#507=CARTESIAN_POINT('',(1.22400774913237,12.1288500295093,12.4400094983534));
#508=CARTESIAN_POINT('',(1.31399171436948,12.2716004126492,12.4308280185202));
#509=CARTESIAN_POINT('',(1.35301037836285,12.3469208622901,12.4266012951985));
#510=CARTESIAN_POINT('',(1.4178302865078,12.5031043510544,12.4193730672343));
#511=CARTESIAN_POINT('',(1.44363199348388,12.5839671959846,12.4163715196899));
#512=CARTESIAN_POINT('',(1.481164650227,12.7485264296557,12.4119503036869));
#513=CARTESIAN_POINT('',(1.49296288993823,12.8322072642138,12.4105230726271));
#514=CARTESIAN_POINT('',(1.50236187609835,13.0003724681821,12.4093888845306));
#515=CARTESIAN_POINT('',(1.49996315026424,13.0848568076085,12.4096818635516));
#516=CARTESIAN_POINT('',(1.48109158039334,13.2517629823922,12.4119480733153));
#517=CARTESIAN_POINT('',(1.46469271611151,13.3341933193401,12.4139124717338));
#518=CARTESIAN_POINT('',(1.41840173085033,13.4951235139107,12.4192864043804));
#519=CARTESIAN_POINT('',(1.38850935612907,13.5736232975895,12.4226959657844));
#520=CARTESIAN_POINT('',(1.31599990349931,13.7246947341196,12.4305861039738));
#521=CARTESIAN_POINT('',(1.27335053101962,13.7972507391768,12.4350693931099));
#522=CARTESIAN_POINT('',(1.17656086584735,13.9342036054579,12.444599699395));
#523=CARTESIAN_POINT('',(1.12242008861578,13.9986001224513,12.4496467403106));
#524=CARTESIAN_POINT('',(1.0037737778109,14.1178355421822,12.4597751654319));
#525=CARTESIAN_POINT('',(0.939204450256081,14.1726109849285,12.464856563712));
#526=CARTESIAN_POINT('',(0.801753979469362,14.2705557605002,12.4744510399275));
#527=CARTESIAN_POINT('',(0.728872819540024,14.3137250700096,12.478964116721));
#528=CARTESIAN_POINT('',(0.576819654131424,14.3872316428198,12.4869159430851));
#529=CARTESIAN_POINT('',(0.497645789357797,14.4175650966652,12.4903543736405));
#530=CARTESIAN_POINT('',(0.335278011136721,14.4644893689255,12.4957665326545));
#531=CARTESIAN_POINT('',(0.252084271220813,14.4810807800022,12.4977403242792));
#532=CARTESIAN_POINT('',(0.0845871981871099,14.4999681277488,12.4999926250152));
#533=CARTESIAN_POINT('',(0.000293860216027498,14.5023515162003,12.5002815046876));
#534=CARTESIAN_POINT('',(-0.167491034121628,14.4929857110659,12.4991593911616));
#535=CARTESIAN_POINT('',(-0.250982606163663,14.4812367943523,12.4977484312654));
#536=CARTESIAN_POINT('',(-0.414537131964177,14.4440125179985,12.4933916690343));
#537=CARTESIAN_POINT('',(-0.494609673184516,14.418578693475,12.4904505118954));
#538=CARTESIAN_POINT('',(-0.649352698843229,14.3547496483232,12.4833627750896));
#539=CARTESIAN_POINT('',(-0.724023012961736,14.316354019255,12.4792161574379));
#540=CARTESIAN_POINT('',(-0.866233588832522,14.2274785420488,12.4701542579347));
#541=CARTESIAN_POINT('',(-0.933738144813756,14.1769419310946,12.4652354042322));
#542=CARTESIAN_POINT('',(-1.05933812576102,14.0652995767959,12.455190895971));
#543=CARTESIAN_POINT('',(-1.11743320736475,14.004193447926,12.4500652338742));
#544=CARTESIAN_POINT('',(-1.22287397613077,13.8727621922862,12.4401529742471));
#545=CARTESIAN_POINT('',(-1.27016181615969,13.8023904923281,12.4353682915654));
#546=CARTESIAN_POINT('',(-1.35224657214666,13.6546524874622,12.4267107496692));
#547=CARTESIAN_POINT('',(-1.38704372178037,13.5772863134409,12.4228378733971));
#548=CARTESIAN_POINT('',(-1.44306498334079,13.4179446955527,12.4164552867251));
#549=CARTESIAN_POINT('',(-1.46432210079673,13.3359809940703,12.4139422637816));
#550=CARTESIAN_POINT('',(-1.49276636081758,13.1696155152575,12.4105542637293));
#551=CARTESIAN_POINT('',(-1.49995410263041,13.0852138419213,12.4096792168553));
#552=CARTESIAN_POINT('',(-1.50004516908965,12.9169436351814,12.4096681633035));
#553=CARTESIAN_POINT('',(-1.49303936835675,12.8330751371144,12.4105210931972));
#554=CARTESIAN_POINT('',(-1.46513424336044,12.6677166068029,12.4138461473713));
#555=CARTESIAN_POINT('',(-1.44423491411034,12.5862265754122,12.4163182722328));
#556=CARTESIAN_POINT('',(-1.38916369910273,12.4279477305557,12.4225998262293));
#557=CARTESIAN_POINT('',(-1.3549958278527,12.3511575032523,12.4264088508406));
#558=CARTESIAN_POINT('',(-1.27436641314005,12.204386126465,12.4349357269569));
#559=CARTESIAN_POINT('',(-1.22790476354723,12.1344050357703,12.4396535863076));
#560=CARTESIAN_POINT('',(-1.12366844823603,12.0027735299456,12.4495027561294));
#561=CARTESIAN_POINT('',(-1.06582601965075,11.9411769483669,12.4546364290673));
#562=CARTESIAN_POINT('',(-0.940610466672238,11.828528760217,12.4647177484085));
#563=CARTESIAN_POINT('',(-0.873235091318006,11.7774796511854,12.4696653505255));
#564=CARTESIAN_POINT('',(-0.730596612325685,11.6872247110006,12.4788360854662));
#565=CARTESIAN_POINT('',(-0.655306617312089,11.6480611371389,12.4830566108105));
#566=CARTESIAN_POINT('',(-0.499211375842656,11.5829881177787,12.4902709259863));
#567=CARTESIAN_POINT('',(-0.418412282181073,11.5570641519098,12.4932660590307));
#568=CARTESIAN_POINT('',(-0.280988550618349,11.5254682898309,12.4969634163));
#569=CARTESIAN_POINT('',(-0.225233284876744,11.5159312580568,12.4980966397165));
#570=CARTESIAN_POINT('',(-0.112993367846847,11.5031959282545,12.4996153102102));
#571=CARTESIAN_POINT('',(-0.0565087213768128,11.4999975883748,12.5000007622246));
#572=CARTESIAN_POINT('',(0.,11.5,12.5));
#573=B_SPLINE_CURVE_WITH_KNOTS('',3,(#495,#496,#497,#498,#499,#500,#501,#502,#503,#504,#505,
#506,#507,#508,#509,#510,#511,#512,#513,#514,#515,#516,#517,#518,#519,#520,#521,#522,#523,#524,
#525,#526,#527,#528,#529,#530,#531,#532,#533,#534,#535,#536,#537,#538,#539,#540,#541,#542,#543,
#544,#545,#546,#547,#548,#549,#550,#551,#552,#553,#554,#555,#556,#557,#558,#559,#560,#561,#562,
#563,#564,#565,#566,#567,#568,#569,#570,#571,#572),.UNSPECIFIED.,.T.,.F.,(4,2,2,2,2,2,2,2,2,2,2,
2,2,2,2,2,2,2,2,2,2,2,2,2,2,2,2,2,2,2,2,2,2,2,2,2,2,2,4),(0.,0.25158967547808,0.503445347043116,
0.755135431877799,1.00678087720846,1.25956936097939,1.51237045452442,1.76595344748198,
2.01952755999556,2.27187819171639,2.5242194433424,2.77523546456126,3.02625620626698,
3.27791786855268,3.52959014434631,3.78286472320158,4.036139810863,4.28949001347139,
4.54282928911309,4.79460761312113,5.04638100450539,5.29739451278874,5.54841593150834,
5.80063460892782,6.05286248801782,6.30641037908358,6.55995352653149,6.81287624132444,
7.06578818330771,7.31708596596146,7.56838383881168,7.81960573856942,8.07082980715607,
8.32359762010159,8.57642521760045,8.83014145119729,9.08357882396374,9.25296714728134,
9.42235435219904),.UNSPECIFIED.);
#574=CARTESIAN_POINT('',(0.,11.5,12.5));
#575=VERTEX_POINT('',#574);
#576=EDGE_CURVE('E44',#575,#575,#573,.T.);
#577=ORIENTED_EDGE('',*,*,#576,.F.);
#578=EDGE_LOOP('',(#577));
#579=FACE_BOUND('',#578,.T.);
#580=CARTESIAN_POINT('',(1.5,13.,-12.4096736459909));
#581=CARTESIAN_POINT('',(1.49999641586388,12.9160704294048,-12.4096748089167));
#582=CARTESIAN_POINT('',(1.49293206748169,12.8320877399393,-12.4105342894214));
#583=CARTESIAN_POINT('',(1.46486159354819,12.6664576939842,-12.4138782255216));
#584=CARTESIAN_POINT('',(1.44384072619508,12.5848129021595,-12.4163643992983));
#585=CARTESIAN_POINT('',(1.38848417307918,12.4262807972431,-12.4226761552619));
#586=CARTESIAN_POINT('',(1.35415731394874,12.3493903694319,-12.426500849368));
#587=CARTESIAN_POINT('',(1.27318168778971,12.2024764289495,-12.4350576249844));
#588=CARTESIAN_POINT('',(1.22653510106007,12.132451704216,-12.4397895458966));
#589=CARTESIAN_POINT('',(1.1219857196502,12.0008801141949,-12.4496550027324));
#590=CARTESIAN_POINT('',(1.06403198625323,11.9393738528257,-12.4547902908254));
#591=CARTESIAN_POINT('',(0.938622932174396,11.826935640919,-12.4648680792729));
#592=CARTESIAN_POINT('',(0.871167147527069,11.7760042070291,-12.4698105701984));
#593=CARTESIAN_POINT('',(0.728414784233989,11.6860167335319,-12.4789637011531));
#594=CARTESIAN_POINT('',(0.653094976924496,11.6469972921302,-12.4831720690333));
#595=CARTESIAN_POINT('',(0.49691288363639,11.5821757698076,-12.4903635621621));
#596=CARTESIAN_POINT('',(0.416050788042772,11.5563732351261,-12.4933467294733));
#597=CARTESIAN_POINT('',(0.251493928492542,11.5188388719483,-12.4977393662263));
#598=CARTESIAN_POINT('',(0.16781473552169,11.5070396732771,-12.4991563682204));
#599=CARTESIAN_POINT('',(-0.000347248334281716,11.4976382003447,-12.5002827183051));
#600=CARTESIAN_POINT('',(-0.0848300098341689,11.5000354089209,-12.4999921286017));
#601=CARTESIAN_POINT('',(-0.251742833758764,11.5189045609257,-12.4977421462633));
#602=CARTESIAN_POINT('',(-0.334181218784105,11.5353040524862,-12.4957913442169));
#603=CARTESIAN_POINT('',(-0.495127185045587,11.581599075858,-12.490449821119));
#604=CARTESIAN_POINT('',(-0.573634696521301,11.6114948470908,-12.4870590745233));
#605=CARTESIAN_POINT('',(-0.724715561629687,11.6840113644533,-12.4792038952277));
#606=CARTESIAN_POINT('',(-0.797273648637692,11.7266636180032,-12.4747368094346));
#607=CARTESIAN_POINT('',(-0.934229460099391,11.8234594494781,-12.465229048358));
#608=CARTESIAN_POINT('',(-0.998626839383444,11.8776035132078,-12.4601883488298));
#609=CARTESIAN_POINT('',(-1.11785860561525,11.9962521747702,-12.4500603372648));
#610=CARTESIAN_POINT('',(-1.17263019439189,12.0608198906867,-12.4449729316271));
#611=CARTESIAN_POINT('',(-1.27056795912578,12.1982657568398,-12.4353563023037));
#612=CARTESIAN_POINT('',(-1.31373410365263,12.2711439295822,-12.4308270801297));
#613=CARTESIAN_POINT('',(-1.38723839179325,12.4231962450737,-12.4228396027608));
#614=CARTESIAN_POINT('',(-1.41757175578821,12.502372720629,-12.4193817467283));
#615=CARTESIAN_POINT('',(-1.46449505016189,12.6647461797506,-12.4139364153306));
#616=CARTESIAN_POINT('',(-1.48108558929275,12.7479429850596,-12.4119488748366));
#617=CARTESIAN_POINT('',(-1.49996964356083,12.9154415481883,-12.4096810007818));
#618=CARTESIAN_POINT('',(-1.50235142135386,12.9997332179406,-12.4093901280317));
#619=CARTESIAN_POINT('',(-1.49298299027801,13.1675143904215,-12.4105206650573));
#620=CARTESIAN_POINT('',(-1.48123305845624,13.2510039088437,-12.411942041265));
#621=CARTESIAN_POINT('',(-1.44400895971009,13.414547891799,-12.4163273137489));
#622=CARTESIAN_POINT('',(-1.41857731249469,13.4946121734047,-12.4192864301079));
#623=CARTESIAN_POINT('',(-1.35475538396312,13.649339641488,-12.4264098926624));
#624=CARTESIAN_POINT('',(-1.31636468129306,13.7240026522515,-12.4305742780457));
#625=CARTESIAN_POINT('',(-1.22749651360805,13.8662081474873,-12.4396643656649));
#626=CARTESIAN_POINT('',(-1.17696103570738,13.9337141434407,-12.4445936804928));
#627=CARTESIAN_POINT('',(-1.06532008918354,14.0593175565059,-12.4546467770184));
#628=CARTESIAN_POINT('',(-1.0042142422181,14.1174146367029,-12.4597705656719));
#629=CARTESIAN_POINT('',(-0.872782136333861,14.2228598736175,-12.4696675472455));
#630=CARTESIAN_POINT('',(-0.802409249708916,14.2701501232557,-12.4744387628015));
#631=CARTESIAN_POINT('',(-0.654668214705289,14.3522391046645,-12.483063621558));
#632=CARTESIAN_POINT('',(-0.577300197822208,14.3870380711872,-12.4869172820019));
#633=CARTESIAN_POINT('',(-0.417959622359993,14.4430605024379,-12.4932640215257));
#634=CARTESIAN_POINT('',(-0.335999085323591,14.4643177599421,-12.4957604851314));
#635=CARTESIAN_POINT('',(-0.16964029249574,14.4927633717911,-12.4991255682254));
#636=CARTESIAN_POINT('',(-0.0852421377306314,14.4999523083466,-12.4999942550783));
#637=CARTESIAN_POINT('',(0.0830300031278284,14.5000469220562,-12.5000056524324));
#638=CARTESIAN_POINT('',(0.166903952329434,14.4930420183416,-12.4991591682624));
#639=CARTESIAN_POINT('',(0.332273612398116,14.4651367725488,-12.4958567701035));
#640=CARTESIAN_POINT('',(0.413769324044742,14.4442364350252,-12.4934008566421));
#641=CARTESIAN_POINT('',(0.572059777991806,14.3891609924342,-12.4871544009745));
#642=CARTESIAN_POINT('',(0.648855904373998,14.3549898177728,-12.4833642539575));
#643=CARTESIAN_POINT('',(0.795637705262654,14.2743519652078,-12.474869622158));
#644=CARTESIAN_POINT('',(0.865623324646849,14.2278851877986,-12.4701651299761));
#645=CARTESIAN_POINT('',(0.99725474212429,14.1236431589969,-12.4603319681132));
#646=CARTESIAN_POINT('',(1.0588476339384,14.0658013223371,-12.4552009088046));
#647=CARTESIAN_POINT('',(1.17148865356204,13.9405884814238,-12.4451123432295));
#648=CARTESIAN_POINT('',(1.22253427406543,13.8732152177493,-12.4401548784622));
#649=CARTESIAN_POINT('',(1.31278537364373,13.7305785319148,-12.4309559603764));
#650=CARTESIAN_POINT('',(1.35194799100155,13.6552878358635,-12.4267171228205));
#651=CARTESIAN_POINT('',(1.41701902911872,13.4991911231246,-12.419466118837));
#652=CARTESIAN_POINT('',(1.44294198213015,13.4183912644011,-12.4164526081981));
#653=CARTESIAN_POINT('',(1.4745350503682,13.2809702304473,-12.4127313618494));
#654=CARTESIAN_POINT('',(1.48407082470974,13.2252186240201,-12.4115903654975));
#655=CARTESIAN_POINT('',(1.49680448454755,13.1129860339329,-12.4100611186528));
#656=CARTESIAN_POINT('',(1.50000241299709,13.0565050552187,-12.4096728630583));
#657=CARTESIAN_POINT('',(1.5,13.,-12.4096736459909));
#658=B_SPLINE_CURVE_WITH_KNOTS('',3,(#580,#581,#582,#583,#584,#585,#586,#587,#588,#589,#590,
#591,#592,#593,#594,#595,#596,#597,#598,#599,#600,#601,#602,#603,#604,#605,#606,#607,#608,#609,
#610,#611,#612,#613,#614,#615,#616,#617,#618,#619,#620,#621,#622,#623,#624,#625,#626,#627,#628,
#629,#630,#631,#632,#633,#634,#635,#636,#637,#638,#639,#640,#641,#642,#643,#644,#645,#646,#647,
#648,#649,#650,#651,#652,#653,#654,#655,#656,#657),.UNSPECIFIED.,.T.,.F.,(4,2,2,2,2,2,2,2,2,2,2,
2,2,2,2,2,2,2,2,2,2,2,2,2,2,2,2,2,2,2,2,2,2,2,2,2,2,2,4),(0.,0.251582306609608,
0.503430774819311,0.755112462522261,1.0067496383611,1.25954776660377,1.5123582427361,
1.76593780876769,2.01950866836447,2.27185458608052,2.52419131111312,2.77523023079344,
3.02627360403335,3.27794222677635,3.52962149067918,3.78288622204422,4.03615163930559,
4.28951130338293,4.54285974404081,4.79463277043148,5.0464008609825,5.29739099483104,
5.54838929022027,5.80061125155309,6.05284224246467,6.30639464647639,6.55994228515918,
6.81285470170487,7.06575665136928,7.31707030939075,7.56838388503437,7.81962308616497,
8.07086432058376,8.32362252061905,8.57644073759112,8.83016031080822,9.08360079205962,
9.25297814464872,9.42235434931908),.UNSPECIFIED.);
#659=CARTESIAN_POINT('',(1.5,13.,-12.4096736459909));
#660=VERTEX_POINT('',#659);
#661=EDGE_CURVE('E141',#660,#660,#658,.T.);
#662=ORIENTED_EDGE('',*,*,#661,.F.);
#663=EDGE_LOOP('',(#662));
#664=FACE_BOUND('',#663,.T.);
#665=CARTESIAN_POINT('',(-12.4096736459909,13.,-1.5));
#666=CARTESIAN_POINT('',(-12.4096748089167,12.9160704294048,-1.49999641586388));
#667=CARTESIAN_POINT('',(-12.4105342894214,12.8320877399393,-1.49293206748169));
#668=CARTESIAN_POINT('',(-12.4138782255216,12.6664576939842,-1.46486159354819));
#669=CARTESIAN_POINT('',(-12.4163643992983,12.5848129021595,-1.44384072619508));
#670=CARTESIAN_POINT('',(-12.4226761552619,12.4262807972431,-1.38848417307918));
#671=CARTESIAN_POINT('',(-12.426500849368,12.3493903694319,-1.35415731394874));
#672=CARTESIAN_POINT('',(-12.4350576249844,12.2024764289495,-1.27318168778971));
#673=CARTESIAN_POINT('',(-12.4397895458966,12.132451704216,-1.22653510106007));
#674=CARTESIAN_POINT('',(-12.4496550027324,12.0008801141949,-1.1219857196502));
#675=CARTESIAN_POINT('',(-12.4547902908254,11.9393738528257,-1.06403198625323));
#676=CARTESIAN_POINT('',(-12.4648680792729,11.826935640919,-0.938622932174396));
#677=CARTESIAN_POINT('',(-12.4698105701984,11.7760042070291,-0.87116714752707));
#678=CARTESIAN_POINT('',(-12.4789637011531,11.6860167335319,-0.72841478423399));
#679=CARTESIAN_POINT('',(-12.4831720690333,11.6469972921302,-0.653094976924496));
#680=CARTESIAN_POINT('',(-12.4903635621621,11.5821757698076,-0.49691288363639));
#681=CARTESIAN_POINT('',(-12.4933467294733,11.5563732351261,-0.416050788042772));
#682=CARTESIAN_POINT('',(-12.4977393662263,11.5188388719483,-0.251493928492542));
#683=CARTESIAN_POINT('',(-12.4991563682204,11.5070396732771,-0.16781473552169));
#684=CARTESIAN_POINT('',(-12.5002827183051,11.4976382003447,0.000347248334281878));
#685=CARTESIAN_POINT('',(-12.4999921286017,11.5000354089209,0.0848300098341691));
#686=CARTESIAN_POINT('',(-12.4977421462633,11.5189045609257,0.251742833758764));
#687=CARTESIAN_POINT('',(-12.4957913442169,11.5353040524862,0.334181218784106));
#688=CARTESIAN_POINT('',(-12.490449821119,11.581599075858,0.495127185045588));
#689=CARTESIAN_POINT('',(-12.4870590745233,11.6114948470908,0.573634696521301));
#690=CARTESIAN_POINT('',(-12.4792038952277,11.6840113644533,0.724715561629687));
#691=CARTESIAN_POINT('',(-12.4747368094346,11.7266636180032,0.797273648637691));
#692=CARTESIAN_POINT('',(-12.465229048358,11.8234594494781,0.934229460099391));
#693=CARTESIAN_POINT('',(-12.4601883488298,11.8776035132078,0.998626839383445));
#694=CARTESIAN_POINT('',(-12.4500603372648,11.9962521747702,1.11785860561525));
#695=CARTESIAN_POINT('',(-12.4449729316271,12.0608198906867,1.17263019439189));
#696=CARTESIAN_POINT('',(-12.4353563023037,12.1982657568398,1.27056795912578));
#697=CARTESIAN_POINT('',(-12.4308270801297,12.2711439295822,1.31373410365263));
#698=CARTESIAN_POINT('',(-12.4228396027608,12.4231962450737,1.38723839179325));
#699=CARTESIAN_POINT('',(-12.4193817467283,12.502372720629,1.41757175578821));
#700=CARTESIAN_POINT('',(-12.4139364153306,12.6647461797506,1.46449505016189));
#701=CARTESIAN_POINT('',(-12.4119488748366,12.7479429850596,1.48108558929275));
#702=CARTESIAN_POINT('',(-12.4096810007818,12.9154415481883,1.49996964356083));
#703=CARTESIAN_POINT('',(-12.4093901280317,12.9997332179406,1.50235142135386));
#704=CARTESIAN_POINT('',(-12.4105206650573,13.1675143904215,1.49298299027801));
#705=CARTESIAN_POINT('',(-12.411942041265,13.2510039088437,1.48123305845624));
#706=CARTESIAN_POINT('',(-12.4163273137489,13.414547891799,1.44400895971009));
#707=CARTESIAN_POINT('',(-12.4192864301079,13.4946121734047,1.41857731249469));
#708=CARTESIAN_POINT('',(-12.4264098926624,13.649339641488,1.35475538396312));
#709=CARTESIAN_POINT('',(-12.4305742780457,13.7240026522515,1.31636468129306));
#710=CARTESIAN_POINT('',(-12.4396643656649,13.8662081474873,1.22749651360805));
#711=CARTESIAN_POINT('',(-12.4445936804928,13.9337141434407,1.17696103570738));
#712=CARTESIAN_POINT('',(-12.4546467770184,14.0593175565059,1.06532008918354));
#713=CARTESIAN_POINT('',(-12.4597705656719,14.1174146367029,1.0042142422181));
#714=CARTESIAN_POINT('',(-12.4696675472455,14.2228598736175,0.872782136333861));
#715=CARTESIAN_POINT('',(-12.4744387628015,14.2701501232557,0.802409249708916));
#716=CARTESIAN_POINT('',(-12.483063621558,14.3522391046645,0.654668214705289));
#717=CARTESIAN_POINT('',(-12.4869172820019,14.3870380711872,0.577300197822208));
#718=CARTESIAN_POINT('',(-12.4932640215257,14.4430605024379,0.417959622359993));
#719=CARTESIAN_POINT('',(-12.4957604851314,14.4643177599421,0.335999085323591));
#720=CARTESIAN_POINT('',(-12.4991255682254,14.4927633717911,0.16964029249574));
#721=CARTESIAN_POINT('',(-12.4999942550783,14.4999523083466,0.0852421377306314));
#722=CARTESIAN_POINT('',(-12.5000056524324,14.5000469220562,-0.0830300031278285));
#723=CARTESIAN_POINT('',(-12.4991591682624,14.4930420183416,-0.166903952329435));
#724=CARTESIAN_POINT('',(-12.4958567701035,14.4651367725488,-0.332273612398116));
#725=CARTESIAN_POINT('',(-12.4934008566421,14.4442364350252,-0.413769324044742));
#726=CARTESIAN_POINT('',(-12.4871544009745,14.3891609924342,-0.572059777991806));
#727=CARTESIAN_POINT('',(-12.4833642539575,14.3549898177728,-0.648855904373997));
#728=CARTESIAN_POINT('',(-12.474869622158,14.2743519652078,-0.795637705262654));
#729=CARTESIAN_POINT('',(-12.4701651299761,14.2278851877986,-0.865623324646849));
#730=CARTESIAN_POINT('',(-12.4603319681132,14.1236431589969,-0.997254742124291));
#731=CARTESIAN_POINT('',(-12.4552009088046,14.0658013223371,-1.0588476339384));
#732=CARTESIAN_POINT('',(-12.4451123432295,13.9405884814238,-1.17148865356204));
#733=CARTESIAN_POINT('',(-12.4401548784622,13.8732152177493,-1.22253427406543));
#734=CARTESIAN_POINT('',(-12.4309559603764,13.7305785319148,-1.31278537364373));
#735=CARTESIAN_POINT('',(-12.4267171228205,13.6552878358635,-1.35194799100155));
#736=CARTESIAN_POINT('',(-12.419466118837,13.4991911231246,-1.41701902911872));
#737=CARTESIAN_POINT('',(-12.4164526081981,13.4183912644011,-1.44294198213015));
#738=CARTESIAN_POINT('',(-12.4127313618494,13.2809702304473,-1.4745350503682));
#739=CARTESIAN_POINT('',(-12.4115903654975,13.2252186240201,-1.48407082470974));
#740=CARTESIAN_POINT('',(-12.4100611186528,13.1129860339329,-1.49680448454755));
#741=CARTESIAN_POINT('',(-12.4096728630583,13.0565050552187,-1.50000241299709));
#742=CARTESIAN_POINT('',(-12.4096736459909,13.,-1.5));
#743=B_SPLINE_CURVE_WITH_KNOTS('',3,(#665,#666,#667,#668,#669,#670,#671,#672,#673,#674,#675,
#676,#677,#678,#679,#680,#681,#682,#683,#684,#685,#686,#687,#688,#689,#690,#691,#692,#693,#694,
#695,#696,#697,#698,#699,#700,#701,#702,#703,#704,#705,#706,#707,#708,#709,#710,#711,#712,#713,
#714,#715,#716,#717,#718,#719,#720,#721,#722,#723,#724,#725,#726,#727,#728,#729,#730,#731,#732,
#733,#734,#735,#736,#737,#738,#739,#740,#741,#742),.UNSPECIFIED.,.T.,.F.,(4,2,2,2,2,2,2,2,2,2,2,
2,2,2,2,2,2,2,2,2,2,2,2,2,2,2,2,2,2,2,2,2,2,2,2,2,2,2,4),(0.,0.25158230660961,0.503430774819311,
0.755112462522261,1.0067496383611,1.25954776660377,1.5123582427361,1.76593780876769,
2.01950866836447,2.27185458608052,2.52419131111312,2.77523023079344,3.02627360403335,
3.27794222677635,3.52962149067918,3.78288622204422,4.03615163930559,4.28951130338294,
4.54285974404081,4.79463277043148,5.0464008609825,5.29739099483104,5.54838929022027,
5.80061125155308,6.05284224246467,6.30639464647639,6.55994228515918,6.81285470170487,
7.06575665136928,7.31707030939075,7.56838388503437,7.81962308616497,8.07086432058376,
8.32362252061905,8.57644073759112,8.83016031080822,9.08360079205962,9.25297814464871,
9.42235434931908),.UNSPECIFIED.);
#744=CARTESIAN_POINT('',(-12.4096736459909,13.,-1.5));
#745=VERTEX_POINT('',#744);
#746=EDGE_CURVE('E81',#745,#745,#743,.T.);
#747=ORIENTED_EDGE('',*,*,#746,.F.);
#748=EDGE_LOOP('',(#747));
#749=FACE_BOUND('',#748,.T.);
#750=CARTESIAN_POINT('',(12.4096736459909,13.,-1.5));
#751=CARTESIAN_POINT('',(12.4096748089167,13.0839295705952,-1.49999641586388));
#752=CARTESIAN_POINT('',(12.4105342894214,13.1679122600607,-1.49293206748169));
#753=CARTESIAN_POINT('',(12.4138782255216,13.3335423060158,-1.46486159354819));
#754=CARTESIAN_POINT('',(12.4163643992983,13.4151870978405,-1.44384072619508));
#755=CARTESIAN_POINT('',(12.4226761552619,13.5737192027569,-1.38848417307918));
#756=CARTESIAN_POINT('',(12.426500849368,13.6506096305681,-1.35415731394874));
#757=CARTESIAN_POINT('',(12.4350576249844,13.7975235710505,-1.27318168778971));
#758=CARTESIAN_POINT('',(12.4397895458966,13.867548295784,-1.22653510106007));
#759=CARTESIAN_POINT('',(12.4496550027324,13.9991198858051,-1.1219857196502));
#760=CARTESIAN_POINT('',(12.4547902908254,14.0606261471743,-1.06403198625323));
#761=CARTESIAN_POINT('',(12.4648680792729,14.173064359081,-0.938622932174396));
#762=CARTESIAN_POINT('',(12.4698105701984,14.2239957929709,-0.87116714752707));
#763=CARTESIAN_POINT('',(12.4789637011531,14.3139832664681,-0.72841478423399));
#764=CARTESIAN_POINT('',(12.4831720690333,14.3530027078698,-0.653094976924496));
#765=CARTESIAN_POINT('',(12.4903635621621,14.4178242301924,-0.49691288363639));
#766=CARTESIAN_POINT('',(12.4933467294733,14.4436267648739,-0.416050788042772));
#767=CARTESIAN_POINT('',(12.4977393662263,14.4811611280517,-0.251493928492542));
#768=CARTESIAN_POINT('',(12.4991563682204,14.4929603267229,-0.16781473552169));
#769=CARTESIAN_POINT('',(12.5002827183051,14.5023617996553,0.000347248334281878));
#770=CARTESIAN_POINT('',(12.4999921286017,14.4999645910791,0.0848300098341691));
#771=CARTESIAN_POINT('',(12.4977421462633,14.4810954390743,0.251742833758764));
#772=CARTESIAN_POINT('',(12.4957913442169,14.4646959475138,0.334181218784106));
#773=CARTESIAN_POINT('',(12.490449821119,14.418400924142,0.495127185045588));
#774=CARTESIAN_POINT('',(12.4870590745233,14.3885051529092,0.573634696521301));
#775=CARTESIAN_POINT('',(12.4792038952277,14.3159886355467,0.724715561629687));
#776=CARTESIAN_POINT('',(12.4747368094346,14.2733363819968,0.797273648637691));
#777=CARTESIAN_POINT('',(12.465229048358,14.1765405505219,0.934229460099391));
#778=CARTESIAN_POINT('',(12.4601883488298,14.1223964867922,0.998626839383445));
#779=CARTESIAN_POINT('',(12.4500603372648,14.0037478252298,1.11785860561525));
#780=CARTESIAN_POINT('',(12.4449729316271,13.9391801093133,1.17263019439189));
#781=CARTESIAN_POINT('',(12.4353563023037,13.8017342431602,1.27056795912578));
#782=CARTESIAN_POINT('',(12.4308270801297,13.7288560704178,1.31373410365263));
#783=CARTESIAN_POINT('',(12.4228396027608,13.5768037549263,1.38723839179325));
#784=CARTESIAN_POINT('',(12.4193817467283,13.497627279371,1.41757175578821));
#785=CARTESIAN_POINT('',(12.4139364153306,13.3352538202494,1.46449505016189));
#786=CARTESIAN_POINT('',(12.4119488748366,13.2520570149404,1.48108558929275));
#787=CARTESIAN_POINT('',(12.4096810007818,13.0845584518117,1.49996964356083));
#788=CARTESIAN_POINT('',(12.4093901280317,13.0002667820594,1.50235142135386));
#789=CARTESIAN_POINT('',(12.4105206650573,12.8324856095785,1.49298299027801));
#790=CARTESIAN_POINT('',(12.411942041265,12.7489960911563,1.48123305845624));
#791=CARTESIAN_POINT('',(12.4163273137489,12.585452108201,1.44400895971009));
#792=CARTESIAN_POINT('',(12.4192864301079,12.5053878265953,1.41857731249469));
#793=CARTESIAN_POINT('',(12.4264098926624,12.350660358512,1.35475538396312));
#794=CARTESIAN_POINT('',(12.4305742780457,12.2759973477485,1.31636468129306));
#795=CARTESIAN_POINT('',(12.4396643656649,12.1337918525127,1.22749651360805));
#796=CARTESIAN_POINT('',(12.4445936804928,12.0662858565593,1.17696103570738));
#797=CARTESIAN_POINT('',(12.4546467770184,11.9406824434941,1.06532008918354));
#798=CARTESIAN_POINT('',(12.4597705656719,11.8825853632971,1.0042142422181));
#799=CARTESIAN_POINT('',(12.4696675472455,11.7771401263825,0.872782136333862));
#800=CARTESIAN_POINT('',(12.4744387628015,11.7298498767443,0.802409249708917));
#801=CARTESIAN_POINT('',(12.483063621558,11.6477608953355,0.654668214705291));
#802=CARTESIAN_POINT('',(12.4869172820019,11.6129619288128,0.577300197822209));
#803=CARTESIAN_POINT('',(12.4932640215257,11.5569394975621,0.417959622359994));
#804=CARTESIAN_POINT('',(12.4957604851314,11.5356822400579,0.335999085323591));
#805=CARTESIAN_POINT('',(12.4991255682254,11.5072366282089,0.16964029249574));
#806=CARTESIAN_POINT('',(12.4999942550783,11.5000476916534,0.0852421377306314));
#807=CARTESIAN_POINT('',(12.5000056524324,11.4999530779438,-0.0830300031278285));
#808=CARTESIAN_POINT('',(12.4991591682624,11.5069579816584,-0.166903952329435));
#809=CARTESIAN_POINT('',(12.4958567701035,11.5348632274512,-0.332273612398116));
#810=CARTESIAN_POINT('',(12.4934008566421,11.5557635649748,-0.413769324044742));
#811=CARTESIAN_POINT('',(12.4871544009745,11.6108390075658,-0.572059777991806));
#812=CARTESIAN_POINT('',(12.4833642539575,11.6450101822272,-0.648855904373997));
#813=CARTESIAN_POINT('',(12.474869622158,11.7256480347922,-0.795637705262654));
#814=CARTESIAN_POINT('',(12.4701651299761,11.7721148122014,-0.865623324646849));
#815=CARTESIAN_POINT('',(12.4603319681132,11.8763568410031,-0.997254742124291));
#816=CARTESIAN_POINT('',(12.4552009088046,11.9341986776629,-1.0588476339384));
#817=CARTESIAN_POINT('',(12.4451123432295,12.0594115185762,-1.17148865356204));
#818=CARTESIAN_POINT('',(12.4401548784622,12.1267847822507,-1.22253427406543));
#819=CARTESIAN_POINT('',(12.4309559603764,12.2694214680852,-1.31278537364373));
#820=CARTESIAN_POINT('',(12.4267171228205,12.3447121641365,-1.35194799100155));
#821=CARTESIAN_POINT('',(12.419466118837,12.5008088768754,-1.41701902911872));
#822=CARTESIAN_POINT('',(12.4164526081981,12.5816087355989,-1.44294198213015));
#823=CARTESIAN_POINT('',(12.4127313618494,12.7190297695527,-1.4745350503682));
#824=CARTESIAN_POINT('',(12.4115903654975,12.7747813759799,-1.48407082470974));
#825=CARTESIAN_POINT('',(12.4100611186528,12.8870139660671,-1.49680448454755));
#826=CARTESIAN_POINT('',(12.4096728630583,12.9434949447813,-1.50000241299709));
#827=CARTESIAN_POINT('',(12.4096736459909,13.,-1.5));
#828=B_SPLINE_CURVE_WITH_KNOTS('',3,(#750,#751,#752,#753,#754,#755,#756,#757,#758,#759,#760,
#761,#762,#763,#764,#765,#766,#767,#768,#769,#770,#771,#772,#773,#774,#775,#776,#777,#778,#779,
#780,#781,#782,#783,#784,#785,#786,#787,#788,#789,#790,#791,#792,#793,#794,#795,#796,#797,#798,
#799,#800,#801,#802,#803,#804,#805,#806,#807,#808,#809,#810,#811,#812,#813,#814,#815,#816,#817,
#818,#819,#820,#821,#822,#823,#824,#825,#826,#827),.UNSPECIFIED.,.T.,.F.,(4,2,2,2,2,2,2,2,2,2,2,
2,2,2,2,2,2,2,2,2,2,2,2,2,2,2,2,2,2,2,2,2,2,2,2,2,2,2,4),(0.,0.25158230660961,0.503430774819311,
0.755112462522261,1.0067496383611,1.25954776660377,1.5123582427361,1.76593780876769,
2.01950866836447,2.27185458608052,2.52419131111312,2.77523023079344,3.02627360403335,
3.27794222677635,3.52962149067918,3.78288622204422,4.03615163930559,4.28951130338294,
4.54285974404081,4.79463277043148,5.0464008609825,5.29739099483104,5.54838929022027,
5.80061125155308,6.05284224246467,6.30639464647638,6.55994228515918,6.81285470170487,
7.06575665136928,7.31707030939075,7.56838388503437,7.81962308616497,8.07086432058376,
8.32362252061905,8.57644073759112,8.83016031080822,9.08360079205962,9.25297814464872,
9.42235434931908),.UNSPECIFIED.);
#829=CARTESIAN_POINT('',(12.4096736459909,13.,-1.5));
#830=VERTEX_POINT('',#829);
#831=EDGE_CURVE('E72',#830,#830,#828,.T.);
#832=ORIENTED_EDGE('',*,*,#831,.F.);
#833=EDGE_LOOP('',(#832));
#834=FACE_BOUND('',#833,.T.);
#835=ORIENTED_EDGE('',*,*,#482,.T.);
#836=EDGE_LOOP('',(#835));
#837=FACE_BOUND('',#836,.T.);
#838=ORIENTED_EDGE('',*,*,#93,.F.);
#839=EDGE_LOOP('',(#838));
#840=FACE_BOUND('',#839,.T.);
#841=ADVANCED_FACE('F89',(#579,#664,#749,#834,#837,#840),#494,.T.);
#842=CARTESIAN_POINT('',(0.,9.,0.));
#843=DIRECTION('',(0.,1.,0.));
#844=DIRECTION('',(0.,0.,1.));
#845=AXIS2_PLACEMENT_3D('',#842,#843,#844);
#846=PLANE('',#845);
#847=CARTESIAN_POINT('',(0.,9.,0.));
#848=DIRECTION('',(0.,1.,0.));
#849=DIRECTION('',(0.,0.,1.));
#850=AXIS2_PLACEMENT_3D('',#847,#848,#849);
#851=CIRCLE('',#850,20.3);
#852=CARTESIAN_POINT('',(0.,9.,20.3));
#853=VERTEX_POINT('',#852);
#854=EDGE_CURVE('E74',#853,#853,#851,.T.);
#855=ORIENTED_EDGE('',*,*,#854,.T.);
#856=EDGE_LOOP('',(#855));
#857=FACE_BOUND('',#856,.T.);
#858=ORIENTED_EDGE('',*,*,#54,.F.);
#859=EDGE_LOOP('',(#858));
#860=FACE_BOUND('',#859,.T.);
#861=ADVANCED_FACE('F159',(#857,#860),#846,.F.);
#862=CARTESIAN_POINT('',(0.,1.,0.));
#863=DIRECTION('',(0.,1.,0.));
#864=DIRECTION('',(0.,0.,1.));
#865=AXIS2_PLACEMENT_3D('',#862,#863,#864);
#866=PLANE('',#865);
#867=CARTESIAN_POINT('',(0.,1.,0.));
#868=DIRECTION('',(0.,1.,0.));
#869=DIRECTION('',(0.,0.,1.));
#870=AXIS2_PLACEMENT_3D('',#867,#868,#869);
#871=CIRCLE('',#870,20.3);
#872=CARTESIAN_POINT('',(0.,1.,20.3));
#873=VERTEX_POINT('',#872);
#874=EDGE_CURVE('E175',#873,#873,#871,.T.);
#875=ORIENTED_EDGE('',*,*,#874,.F.);
#876=EDGE_LOOP('',(#875));
#877=FACE_BOUND('',#876,.T.);
#878=ORIENTED_EDGE('',*,*,#42,.T.);
#879=EDGE_LOOP('',(#878));
#880=FACE_BOUND('',#879,.T.);
#881=ADVANCED_FACE('F181',(#877,#880),#866,.T.);
#882=CARTESIAN_POINT('',(0.,9.,0.));
#883=DIRECTION('',(0.,-1.,0.));
#884=DIRECTION('',(0.,0.,-1.));
#885=AXIS2_PLACEMENT_3D('',#882,#883,#884);
#886=CYLINDRICAL_SURFACE('',#885,20.3);
#887=ORIENTED_EDGE('',*,*,#854,.F.);
#888=EDGE_LOOP('',(#887));
#889=FACE_BOUND('',#888,.T.);
#890=ORIENTED_EDGE('',*,*,#874,.T.);
#891=EDGE_LOOP('',(#890));
#892=FACE_BOUND('',#891,.T.);
#893=ADVANCED_FACE('F99',(#889,#892),#886,.T.);
#894=CARTESIAN_POINT('',(-21.8,13.,0.));
#895=DIRECTION('',(1.,0.,0.));
#896=DIRECTION('',(0.,0.,-1.));
#897=AXIS2_PLACEMENT_3D('',#894,#895,#896);
#898=CYLINDRICAL_SURFACE('',#897,1.5);
#899=ORIENTED_EDGE('',*,*,#831,.T.);
#900=EDGE_LOOP('',(#899));
#901=FACE_BOUND('',#900,.T.);
#902=ORIENTED_EDGE('',*,*,#459,.F.);
#903=EDGE_LOOP('',(#902));
#904=FACE_BOUND('',#903,.T.);
#905=ADVANCED_FACE('F98',(#901,#904),#898,.F.);
#906=ORIENTED_EDGE('',*,*,#746,.T.);
#907=EDGE_LOOP('',(#906));
#908=FACE_BOUND('',#907,.T.);
#909=ORIENTED_EDGE('',*,*,#374,.F.);
#910=EDGE_LOOP('',(#909));
#911=FACE_BOUND('',#910,.T.);
#912=ADVANCED_FACE('F94',(#908,#911),#898,.F.);
#913=CARTESIAN_POINT('',(0.,13.,-21.8));
#914=DIRECTION('',(0.,0.,1.));
#915=DIRECTION('',(1.,0.,0.));
#916=AXIS2_PLACEMENT_3D('',#913,#914,#915);
#917=CYLINDRICAL_SURFACE('',#916,1.5);
#918=ORIENTED_EDGE('',*,*,#661,.T.);
#919=EDGE_LOOP('',(#918));
#920=FACE_BOUND('',#919,.T.);
#921=ORIENTED_EDGE('',*,*,#289,.F.);
#922=EDGE_LOOP('',(#921));
#923=FACE_BOUND('',#922,.T.);
#924=ADVANCED_FACE('F92',(#920,#923),#917,.F.);
#925=ORIENTED_EDGE('',*,*,#576,.T.);
#926=EDGE_LOOP('',(#925));
#927=FACE_BOUND('',#926,.T.);
#928=ORIENTED_EDGE('',*,*,#204,.F.);
#929=EDGE_LOOP('',(#928));
#930=FACE_BOUND('',#929,.T.);
#931=ADVANCED_FACE('F96',(#927,#930),#917,.F.);
#932=CLOSED_SHELL('',(#46,#69,#97,#117,#469,#489,#841,#861,#881,#893,#905,#912,#924,#931));
#933=MANIFOLD_SOLID_BREP('B2',#932);
#934=ADVANCED_BREP_SHAPE_REPRESENTATION('',(#18,#933),#14);
#935=SHAPE_DEFINITION_REPRESENTATION(#9,#934);
ENDSEC;
END-ISO-10303-21;
